# Custom LEF file with two endcap definitions, to test the correct orientation
# when using specific endcaps for left and right edges.

VERSION 5.6 ;
BUSBITCHARS "[]" ;
DIVIDERCHAR "/" ;

UNITS
  DATABASE MICRONS 2000 ;
END UNITS

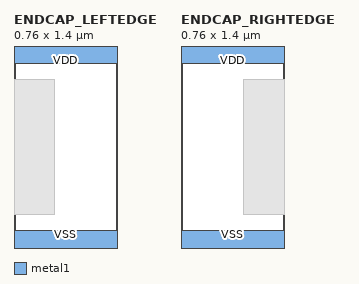
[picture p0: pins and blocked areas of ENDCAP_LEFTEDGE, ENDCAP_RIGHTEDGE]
MACRO ENDCAP_LEFTEDGE
  PROPERTY LEF58_CLASS " CLASS ENDCAP LEFTEDGE ; " ;
  ORIGIN 0 0 ;
  FOREIGN ENDCAP_LEFTEDGE 0 0 ;
  SIZE 0.76 BY 1.4 ;
  SYMMETRY X Y ;
  SITE FreePDK45_38x28_10R_NP_162NW_34O ;
  PIN VDD
    DIRECTION INOUT ;
    USE POWER ;
    SHAPE ABUTMENT ;
    PORT
      LAYER metal1 ;
        RECT 0 1.315 0.76 1.485 ;
    END
  END VDD
  PIN VSS
    DIRECTION INOUT ;
    USE GROUND ;
    SHAPE ABUTMENT ;
    PORT
      LAYER metal1 ;
        RECT 0 -0.085 0.76 0.085 ;
    END
  END VSS
  OBS
    LAYER metal2 ;
      RECT 0.0 0.2 0.3 1.2 ;
  END
END ENDCAP_LEFTEDGE

MACRO ENDCAP_RIGHTEDGE
  PROPERTY LEF58_CLASS " CLASS ENDCAP RIGHTEDGE ; " ;
  ORIGIN 0 0 ;
  FOREIGN ENDCAP_RIGHTEDGE 0 0 ;
  SIZE 0.76 BY 1.4 ;
  SYMMETRY X Y ;
  SITE FreePDK45_38x28_10R_NP_162NW_34O ;
  PIN VDD
    DIRECTION INOUT ;
    USE POWER ;
    SHAPE ABUTMENT ;
    PORT
      LAYER metal1 ;
        RECT 0 1.315 0.76 1.485 ;
    END
  END VDD
  PIN VSS
    DIRECTION INOUT ;
    USE GROUND ;
    SHAPE ABUTMENT ;
    PORT
      LAYER metal1 ;
        RECT 0 -0.085 0.76 0.085 ;
    END
  END VSS
  OBS
    LAYER metal2 ;
      RECT 0.46 0.2 0.76 1.2 ;
  END
END ENDCAP_RIGHTEDGE

END LIBRARY
